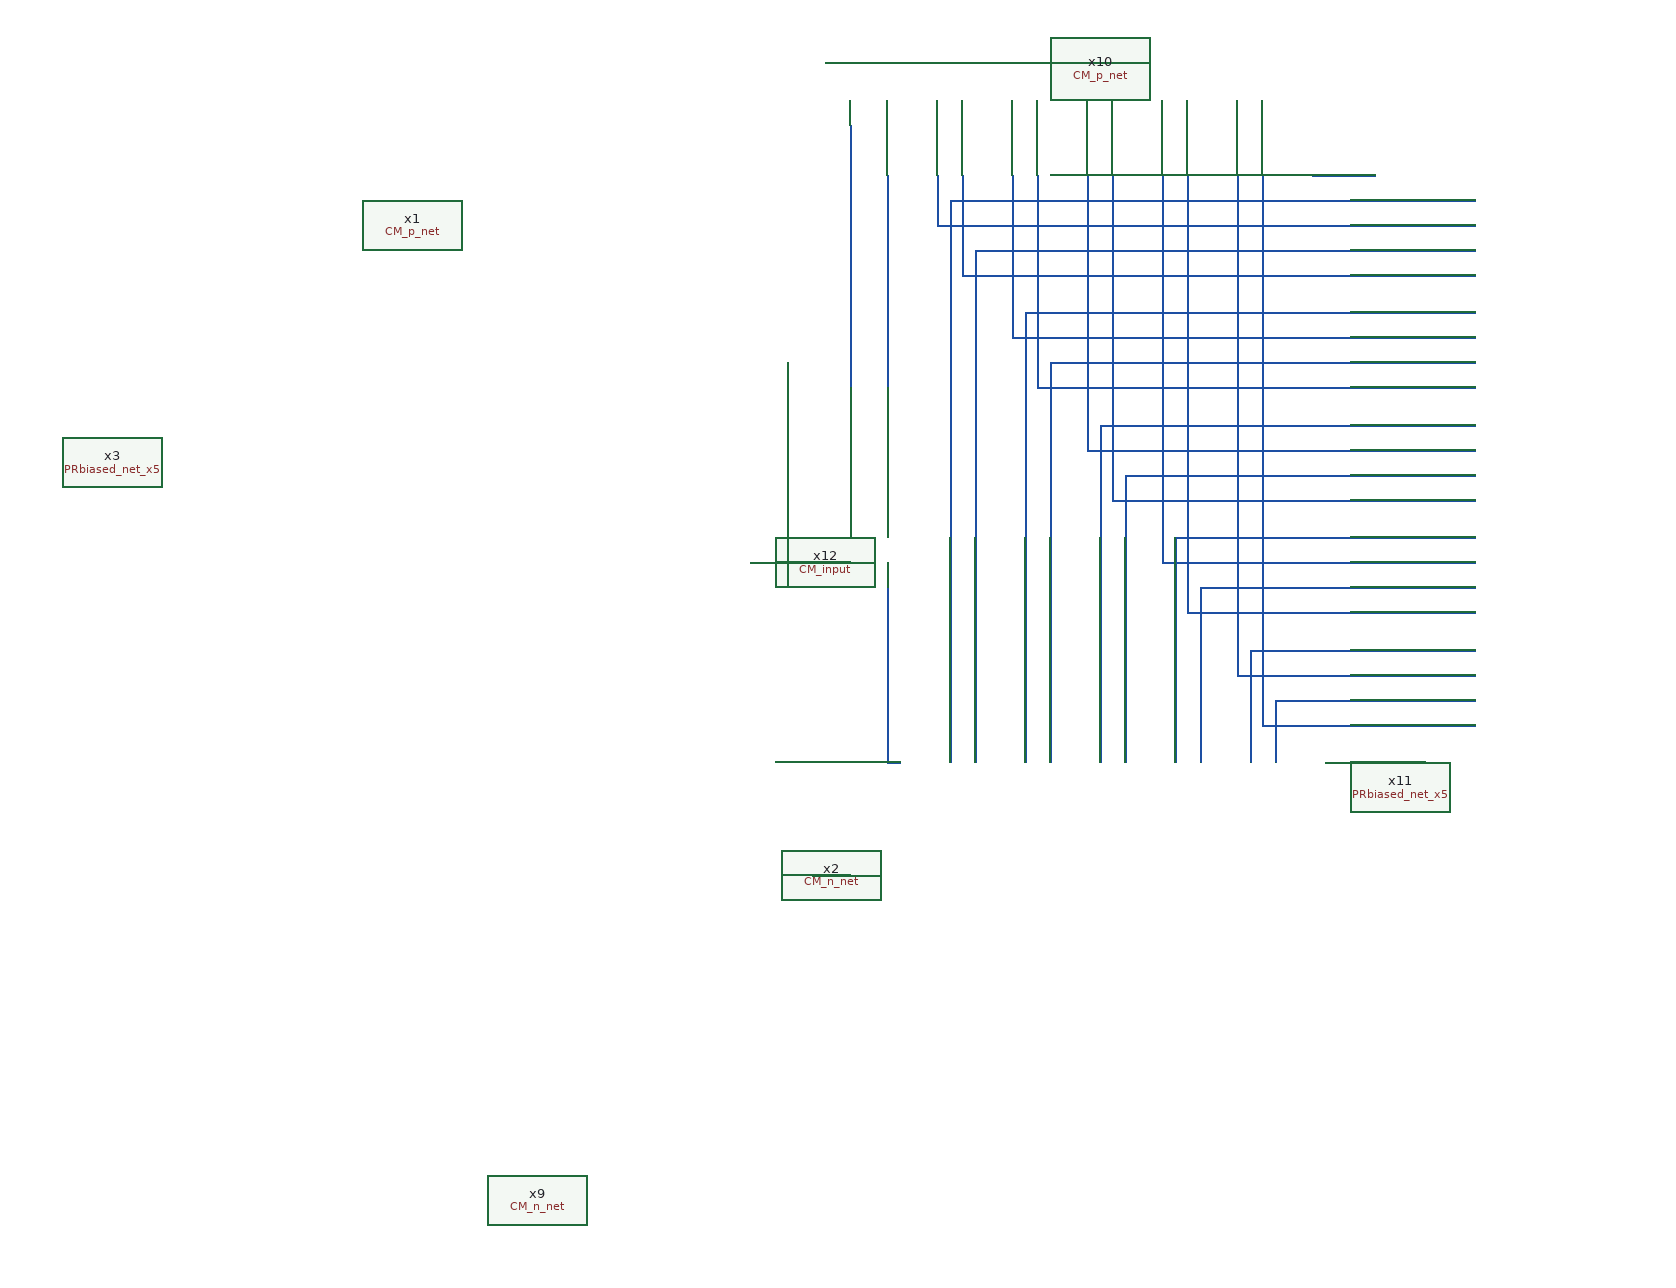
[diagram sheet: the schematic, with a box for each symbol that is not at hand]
v {xschem version=3.4.5 file_version=1.2
}
G {}
K {}
V {}
S {}
E {}
N 300 -550 300 -530 {
lab=#net1}
N 320 -140 350 -140 {
lab=#net2}
N 330 -790 350 -790 {
lab=#net3}
N 380 -390 380 -370 {
lab=#net4}
N 380 -310 380 -230 {
lab=#net4}
N 380 -560 380 -530 {
lab=#net5}
N 380 -700 380 -620 {
lab=#net5}
N 380 -230 390 -230 {
lab=#net4}
N 430 -680 850 -680 {
lab=#net6}
N 450 -640 850 -640 {
lab=#net7}
N 490 -590 850 -590 {
lab=#net8}
N 490 -590 490 -230 {
lab=#net8}
N 550 -500 850 -500 {
lab=#net9}
N 550 -500 550 -230 {
lab=#net9}
N 570 -460 570 -230 {
lab=#net10}
N 570 -460 850 -460 {
lab=#net10}
N 610 -410 850 -410 {
lab=#net11}
N 610 -410 610 -230 {
lab=#net11}
N 630 -370 850 -370 {
lab=#net12}
N 630 -370 630 -230 {
lab=#net12}
N 670 -320 670 -230 {
lab=#net13}
N 670 -320 850 -320 {
lab=#net13}
N 690 -280 850 -280 {
lab=#net14}
N 690 -280 690 -230 {
lab=#net14}
N 510 -550 850 -550 {
lab=#net15}
N 510 -520 510 -230 {
lab=#net15}
N 420 -660 850 -660 {
lab=#net16}
N 420 -700 420 -660 {
lab=#net16}
N 440 -620 850 -620 {
lab=#net17}
N 440 -700 440 -620 {
lab=#net17}
N 480 -570 850 -570 {
lab=#net18}
N 480 -700 480 -570 {
lab=#net18}
N 500 -530 850 -530 {
lab=#net19}
N 500 -700 500 -530 {
lab=#net19}
N 540 -480 850 -480 {
lab=#net20}
N 540 -700 540 -480 {
lab=#net20}
N 560 -440 850 -440 {
lab=#net21}
N 560 -700 560 -440 {
lab=#net21}
N 600 -390 850 -390 {
lab=#net22}
N 600 -700 600 -390 {
lab=#net22}
N 620 -350 850 -350 {
lab=#net23}
N 620 -700 620 -350 {
lab=#net23}
N 660 -300 850 -300 {
lab=#net24}
N 660 -700 660 -300 {
lab=#net24}
N 680 -260 850 -260 {
lab=#net25}
N 680 -700 680 -260 {
lab=#net25}
N 270 -390 350 -390 {
lab=#net26}
N 350 -740 350 -530 {
lab=#net27}
N 430 -680 430 -300 {
lab=#net6}
N 450 -640 450 -300 {
lab=#net7}
N 730 -230 810 -230 {
lab=#net28}
N 720 -700 770 -700 {
lab=#net29}
N 510 -550 510 -520 {
lab=#net15}
N 430 -300 430 -230 {
lab=#net6}
N 450 -300 450 -230 {
lab=#net7}
N 380 -370 380 -310 {
lab=#net4}
N 380 -620 380 -560 {
lab=#net5}
C {CurrentMirrors/CM_n_net.sym} 100 120 0 0 {name=x9}
C {CurrentMirrors/CM_p_net.sym} 590 -660 0 0 {name=x10}
C {PseudoResistor/PRbiased_net_x5.sym} 860 -480 1 0 {name=x11}
C {CurrentMirrors/CM_input.sym} 370 -470 0 0 {name=x12}
C {CurrentMirrors/CM_p_net.sym} 0 -660 0 1 {name=x1}
C {CurrentMirrors/CM_n_net.sym} 510 120 0 1 {name=x2}
C {PseudoResistor/PRbiased_net_x5.sym} -240 -470 3 1 {name=x3}
